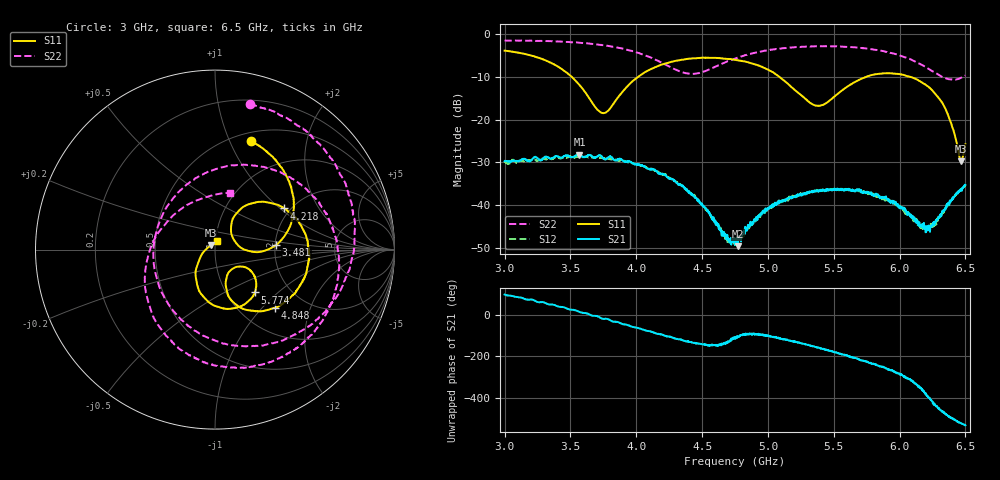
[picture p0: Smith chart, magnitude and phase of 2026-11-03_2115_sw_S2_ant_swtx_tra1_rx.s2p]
! HEWLETT PACKARD,8720ES,MY41003347,7.72, via bringup/vna_tests.py
! sw_S2_ant_swtx_tra1_rx
! measured 2026-11-03 21:16:18, 1601 points, 3000000000-6500000000 Hz, IF bandwidth 1000 Hz, source -40.00 dBm, kit CALK35MD
! board A, CTRL bits {'tr_a': 1} set before each sweep
# HZ S RI R 50
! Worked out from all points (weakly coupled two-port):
!   1601 points, 3 GHz to 6.5 GHz, reference 50 ohm
!   highest |S21| = -28.22 dB at 3.569 GHz (marker M1); lowest = -49.6 dB at 4.77 GHz (marker M2)
!   lowest |S11| = -29.8 dB at 6.467 GHz (marker M3), VSWR 1.07, Z = 47.9 + j2.36 ohm
!   |S11| at or under -10 dB: 3.508 GHz to 4.016 GHz (508.1 MHz wide, 13.5 % of centre); 5.085 GHz to 5.749 GHz (663.5 MHz wide, 12.2 % of centre); 6.074 GHz to end of sweep
!   |S22| runs from -10.7 to -1.5 dB; largest |S21 - S12| = 0.0036
!   S11 on the Smith chart (normalised r, x): 3 GHz: 0.59, +1.21; 3.481 GHz: 2.03, +0.13; 4.218 GHz: 1.86, +1.07; 4.848 GHz: 1.43, -1.18; 5.774 GHz: 1.35, -0.72; 6.5 GHz: 1.02, +0.10
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3e9  0.2032 0.6043  -0.00618 0.032  -0.00466 0.0318  0.1962 0.813
3.255938e9  0.4358 0.2965  0.0154 0.0308  0.0132 0.0303  0.5671 0.6028
3.48125e9  0.3414 0.0275  0.0328 0.0194  0.0308 0.0201  0.7584 0.2667
3.56875e9  0.2524 -0.0125  0.0372 0.0111  0.0349 0.0107  0.7794 0.1124
3.584062e9  0.2365 -0.0141  0.036 0.00859  0.0349 0.0093  0.7778 0.085
3.759062e9  0.099 0.0661  0.0328 -0.0104  0.0337 -0.00971  0.6977 -0.2299
3.98e9  0.1591 0.2393  0.0166 -0.0258  0.0174 -0.0257  0.3509 -0.5138
4.168125e9  0.3397 0.2524  0.00011 -0.0236  -5.05e-05 -0.0246  -0.0709 -0.476
4.218438e9  0.3855 0.2296  -0.00333 -0.022  -0.00365 -0.0225  -0.1716 -0.4058
4.448125e9  0.5186 0.0269  -0.00857 -0.00856  -0.00924 -0.00867  -0.3214 0.1183
4.599062e9  0.5069 -0.136  -0.00534 -0.00359  -0.00525 -0.00342  -0.1047 0.3996
4.75e9  0.4216 -0.2649  -0.000988 -0.00327  -0.000877 -0.00331  0.2087 0.4688
4.769688e9  0.403 -0.2812  -0.000661 -0.00326  -0.000946 -0.00379  0.2491 0.4627
4.848438e9  0.3346 -0.3237  -0.000139 -0.00589  -7.89e-05 -0.0054  0.3976 0.4109
5.075938e9  0.1142 -0.3033  -0.00364 -0.00986  -0.00349 -0.0102  0.6581 0.1094
5.334062e9  0.0716 -0.1343  -0.0123 -0.00728  -0.0126 -0.00746  0.6483 -0.2997
5.77375e9  0.2219 -0.2385  -0.00833 0.011  -0.00833 0.0111  0.1052 -0.6564
5.918125e9  0.1411 -0.3165  -0.00126 0.0117  -0.00103 0.0112  -0.1379 -0.5908
6.213438e9  -0.0891 -0.2289  0.00427 -0.00302  0.00441 -0.00263  -0.3855 -0.0952
6.346875e9  -0.0999 -0.0907  -0.0043 -0.0083  -0.00449 -0.00788  -0.2475 0.1759
6.467188e9  -0.0211 0.0246  -0.0145 -0.00365  -0.0149 -0.00391  0.00632 0.3073
6.5e9  0.0135 0.0496  -0.0171 -0.0016  -0.0171 -0.00111  0.0834 0.3153
